One B-rep face of a CAD part: STEP entity #175.
In plain terms, the planar face has unit normal (1, 0, 0).
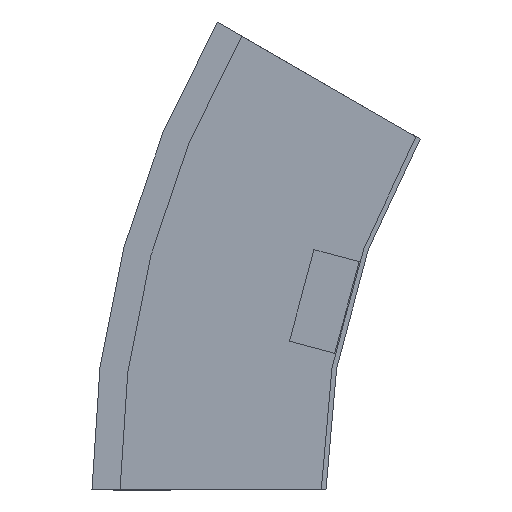
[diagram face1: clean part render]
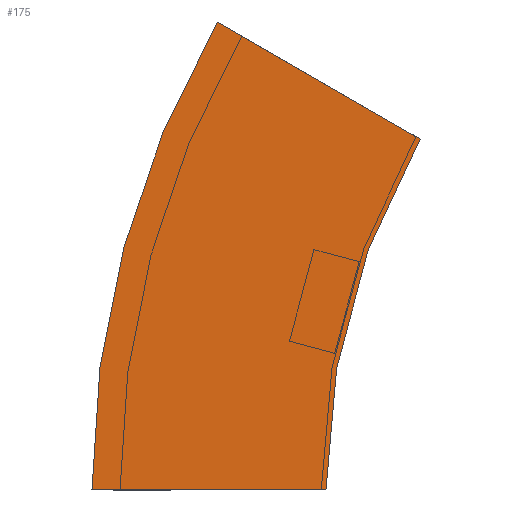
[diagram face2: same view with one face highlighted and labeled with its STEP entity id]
Its self-contained STEP definition (entity closure, numbers rounded to 3 decimals):
#5 = DIRECTION ( 'NONE',  ( 1., 0., 0. ) ) ;
#70 = CIRCLE ( 'NONE', #384, 300. ) ;
#99 = CARTESIAN_POINT ( 'NONE',  ( 0., -40.192, 150. ) ) ;
#109 = CARTESIAN_POINT ( 'NONE',  ( 0., 100., 0. ) ) ;
#111 = DIRECTION ( 'NONE',  ( 0., 1., 0. ) ) ;
#112 = DIRECTION ( 'NONE',  ( 1., 0., 0. ) ) ;
#115 = VECTOR ( 'NONE', #292, 1000. ) ;
#123 = CARTESIAN_POINT ( 'NONE',  ( 0., 46.41, 200. ) ) ;
#131 = CARTESIAN_POINT ( 'NONE',  ( 0., 0., 0. ) ) ;
#155 = CARTESIAN_POINT ( 'NONE',  ( 0., -300., 0. ) ) ;
#170 = LINE ( 'NONE', #131, #115 ) ;
#175 = ADVANCED_FACE ( 'NONE', ( #199 ), #271, .T. ) ;
#176 = EDGE_LOOP ( 'NONE', ( #545, #338, #474, #506 ) ) ;
#199 = FACE_OUTER_BOUND ( 'NONE', #176, .T. ) ;
#200 = VERTEX_POINT ( 'NONE', #109 ) ;
#236 = EDGE_CURVE ( 'NONE', #200, #284, #400, .T. ) ;
#241 = AXIS2_PLACEMENT_3D ( 'NONE', #322, #5, #320 ) ;
#248 = DIRECTION ( 'NONE',  ( 0., 0.866, 0.5 ) ) ;
#270 = CARTESIAN_POINT ( 'NONE',  ( 0., 0., 0. ) ) ;
#271 = PLANE ( 'NONE',  #477 ) ;
#281 = VECTOR ( 'NONE', #248, 1000. ) ;
#284 = VERTEX_POINT ( 'NONE', #123 ) ;
#292 = DIRECTION ( 'NONE',  ( 0., 1., 0. ) ) ;
#313 = EDGE_CURVE ( 'NONE', #379, #284, #473, .T. ) ;
#320 = DIRECTION ( 'NONE',  ( 0., 1., 0. ) ) ;
#322 = CARTESIAN_POINT ( 'NONE',  ( 0., -300., 0. ) ) ;
#324 = DIRECTION ( 'NONE',  ( 1., 0., 0. ) ) ;
#338 = ORIENTED_EDGE ( 'NONE', *, *, #313, .F. ) ;
#352 = EDGE_CURVE ( 'NONE', #532, #200, #170, .T. ) ;
#371 = DIRECTION ( 'NONE',  ( 0., 0., -1. ) ) ;
#379 = VERTEX_POINT ( 'NONE', #99 ) ;
#384 = AXIS2_PLACEMENT_3D ( 'NONE', #155, #324, #111 ) ;
#400 = CIRCLE ( 'NONE', #241, 400. ) ;
#473 = LINE ( 'NONE', #548, #281 ) ;
#474 = ORIENTED_EDGE ( 'NONE', *, *, #556, .F. ) ;
#477 = AXIS2_PLACEMENT_3D ( 'NONE', #543, #112, #371 ) ;
#506 = ORIENTED_EDGE ( 'NONE', *, *, #352, .T. ) ;
#532 = VERTEX_POINT ( 'NONE', #270 ) ;
#543 = CARTESIAN_POINT ( 'NONE',  ( 0., 0., 0. ) ) ;
#545 = ORIENTED_EDGE ( 'NONE', *, *, #236, .T. ) ;
#548 = CARTESIAN_POINT ( 'NONE',  ( 0., -40.192, 150. ) ) ;
#556 = EDGE_CURVE ( 'NONE', #532, #379, #70, .T. ) ;
